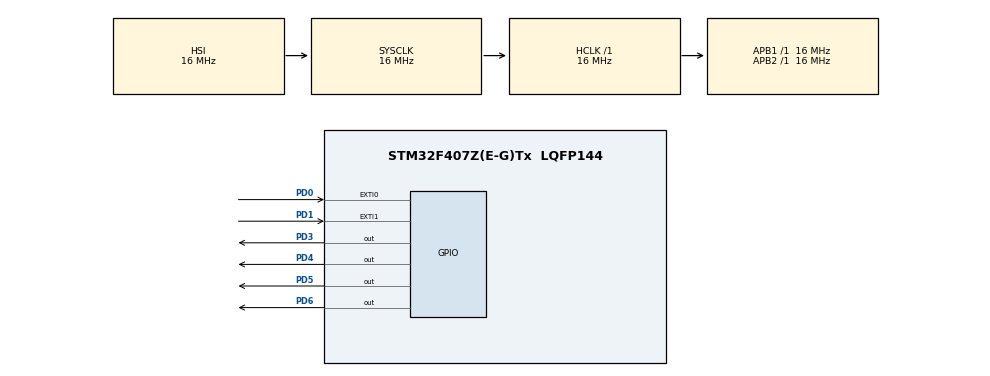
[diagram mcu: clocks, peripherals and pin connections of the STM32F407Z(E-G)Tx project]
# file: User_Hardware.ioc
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Mcu.Family=STM32F4
Mcu.Name=STM32F407Z(E-G)Tx
Mcu.Package=LQFP144
NVIC.PriorityGroup=NVIC_PRIORITYGROUP_4
PD0.Signal=GPXTI0
PD1.Signal=GPXTI1
PD3.Signal=GPIO_Output
PD4.Signal=GPIO_Output
PD5.Signal=GPIO_Output
PD6.Signal=GPIO_Output
ProjectManager.HeapSize=0x200
ProjectManager.StackSize=0x400
ProjectManager.TargetToolchain=Makefile
RCC.AHBFreq_Value=16000000
RCC.APB1Freq_Value=16000000
RCC.APB2Freq_Value=16000000
RCC.CortexFreq_Value=16000000
RCC.HSE_VALUE=25000000
RCC.HSI_VALUE=16000000
RCC.LSE_VALUE=32768
RCC.SYSCLKFreq_VALUE=16000000
RCC.VCOOutputFreq_Value=192000000
board=User_Hardware

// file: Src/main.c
/**
  ******************************************************************************
  * File Name          : main.c
  * Description        : Main program body
  ******************************************************************************
  ** This notice applies to any and all portions of this file
  * that are not between comment pairs USER CODE BEGIN and
  * USER CODE END. Other portions of this file, whether
  * inserted by the user or by software development tools
  * are owned by their respective copyright owners.
  *
  * COPYRIGHT(c) 2017 STMicroelectronics
  *
  * Redistribution and use in source and binary forms, with or without modification,
  * are permitted provided that the following conditions are met:
  *   1. Redistributions of source code must retain the above copyright notice,
  *      this list of conditions and the following disclaimer.
  *   2. Redistributions in binary form must reproduce the above copyright notice,
  *      this list of conditions and the following disclaimer in the documentation
  *      and/or other materials provided with the distribution.
  *   3. Neither the name of STMicroelectronics nor the names of its contributors
  *      may be used to endorse or promote products derived from this software
  *      without specific prior written permission.
  *
  * THIS SOFTWARE IS PROVIDED BY THE COPYRIGHT HOLDERS AND CONTRIBUTORS "AS IS"
  * AND ANY EXPRESS OR IMPLIED WARRANTIES, INCLUDING, BUT NOT LIMITED TO, THE
  * IMPLIED WARRANTIES OF MERCHANTABILITY AND FITNESS FOR A PARTICULAR PURPOSE ARE
  * DISCLAIMED. IN NO EVENT SHALL THE COPYRIGHT HOLDER OR CONTRIBUTORS BE LIABLE
  * FOR ANY DIRECT, INDIRECT, INCIDENTAL, SPECIAL, EXEMPLARY, OR CONSEQUENTIAL
  * DAMAGES (INCLUDING, BUT NOT LIMITED TO, PROCUREMENT OF SUBSTITUTE GOODS OR
  * SERVICES; LOSS OF USE, DATA, OR PROFITS; OR BUSINESS INTERRUPTION) HOWEVER
  * CAUSED AND ON ANY THEORY OF LIABILITY, WHETHER IN CONTRACT, STRICT LIABILITY,
  * OR TORT (INCLUDING NEGLIGENCE OR OTHERWISE) ARISING IN ANY WAY OUT OF THE USE
  * OF THIS SOFTWARE, EVEN IF ADVISED OF THE POSSIBILITY OF SUCH DAMAGE.
  *
  ******************************************************************************
  */
#include "main.h"
#include "stm32f4xx_hal.h"

/* USER CODE BEGIN PV */
/* Private variables ---------------------------------------------------------*/

/* USER CODE END PV */

void SystemClock_Config(void);
static void MX_GPIO_Init(void);

/* USER CODE BEGIN PFP */
/* Private function prototypes -----------------------------------------------*/

/* USER CODE END PFP */

int main(void)
{

  /* MCU Configuration----------------------------------------------------------*/

  /* Reset of all peripherals, Initializes the Flash interface and the Systick. */
  HAL_Init();

  /* Configure the system clock */
  SystemClock_Config();

  /* Initialize all configured peripherals */
  MX_GPIO_Init();

  /* Infinite loop */
  while (1)
  {
    HAL_GPIO_TogglePin(GPIOF, GPIO_PIN_3|GPIO_PIN_4|GPIO_PIN_5|GPIO_PIN_2);
    HAL_GPIO_TogglePin(GPIOC, GPIO_PIN_13);
    HAL_Delay(500);

  }

}

/** System Clock Configuration
*/
void SystemClock_Config(void)
{

  RCC_OscInitTypeDef RCC_OscInitStruct;
  RCC_ClkInitTypeDef RCC_ClkInitStruct;

    /**Configure the main internal regulator output voltage
    */
  __HAL_RCC_PWR_CLK_ENABLE();

  __HAL_PWR_VOLTAGESCALING_CONFIG(PWR_REGULATOR_VOLTAGE_SCALE1);

    /**Initializes the CPU, AHB and APB busses clocks
    */
  RCC_OscInitStruct.OscillatorType = RCC_OSCILLATORTYPE_HSI;
  RCC_OscInitStruct.HSIState = RCC_HSI_ON;
  RCC_OscInitStruct.HSICalibrationValue = 16;
  RCC_OscInitStruct.PLL.PLLState = RCC_PLL_NONE;
  if (HAL_RCC_OscConfig(&RCC_OscInitStruct) != HAL_OK)
  {
    _Error_Handler(__FILE__, __LINE__);
  }

    /**Initializes the CPU, AHB and APB busses clocks
    */
  RCC_ClkInitStruct.ClockType = RCC_CLOCKTYPE_HCLK|RCC_CLOCKTYPE_SYSCLK
                              |RCC_CLOCKTYPE_PCLK1|RCC_CLOCKTYPE_PCLK2;
  RCC_ClkInitStruct.SYSCLKSource = RCC_SYSCLKSOURCE_HSI;
  RCC_ClkInitStruct.AHBCLKDivider = RCC_SYSCLK_DIV1;
  RCC_ClkInitStruct.APB1CLKDivider = RCC_HCLK_DIV1;
  RCC_ClkInitStruct.APB2CLKDivider = RCC_HCLK_DIV1;

  if (HAL_RCC_ClockConfig(&RCC_ClkInitStruct, FLASH_LATENCY_0) != HAL_OK)
  {
    _Error_Handler(__FILE__, __LINE__);
  }

    /**Configure the Systick interrupt time
    */
  HAL_SYSTICK_Config(HAL_RCC_GetHCLKFreq()/1000);

    /**Configure the Systick
    */
  HAL_SYSTICK_CLKSourceConfig(SYSTICK_CLKSOURCE_HCLK);

  /* SysTick_IRQn interrupt configuration */
  HAL_NVIC_SetPriority(SysTick_IRQn, 0, 0);
}

/** Configure pins as
        * Analog
        * Input
        * Output
        * EVENT_OUT
        * EXTI
*/
static void MX_GPIO_Init(void)
{

  GPIO_InitTypeDef GPIO_InitStruct;

  /* GPIO Ports Clock Enable */
  __HAL_RCC_GPIOF_CLK_ENABLE();
  __HAL_RCC_GPIOC_CLK_ENABLE();
  /*Configure GPIO pin Output Level */
  HAL_GPIO_WritePin(GPIOF, GPIO_PIN_3|GPIO_PIN_4|GPIO_PIN_5|GPIO_PIN_2, GPIO_PIN_RESET);
  HAL_GPIO_WritePin(GPIOC, GPIO_PIN_13, GPIO_PIN_RESET);
  /*Configure GPIO pins : PD0 PD1 */
  GPIO_InitStruct.Pin = GPIO_PIN_0|GPIO_PIN_1;
  GPIO_InitStruct.Mode = GPIO_MODE_IT_RISING;
  GPIO_InitStruct.Pull = GPIO_NOPULL;
  HAL_GPIO_Init(GPIOF, &GPIO_InitStruct);

  /*Configure GPIO pins : PD3 PD4 PD5 PD6 */
  GPIO_InitStruct.Pin = GPIO_PIN_3|GPIO_PIN_4|GPIO_PIN_5|GPIO_PIN_2;
  GPIO_InitStruct.Mode = GPIO_MODE_OUTPUT_PP;
  GPIO_InitStruct.Pull = GPIO_NOPULL;
  GPIO_InitStruct.Speed = GPIO_SPEED_FREQ_LOW;
  HAL_GPIO_Init(GPIOF, &GPIO_InitStruct);

  /* Configure GPIO pin: C13*/
  GPIO_InitStruct.Pin = GPIO_PIN_13;
  GPIO_InitStruct.Mode = GPIO_MODE_OUTPUT_PP;
  GPIO_InitStruct.Pull = GPIO_NOPULL;
  GPIO_InitStruct.Speed = GPIO_SPEED_FREQ_LOW;
  HAL_GPIO_Init(GPIOC, &GPIO_InitStruct);

}

void _Error_Handler(char * file, int line)
{
  while(1)
  {
  }
}

/************************ (C) COPYRIGHT STMicroelectronics *****END OF FILE****/
